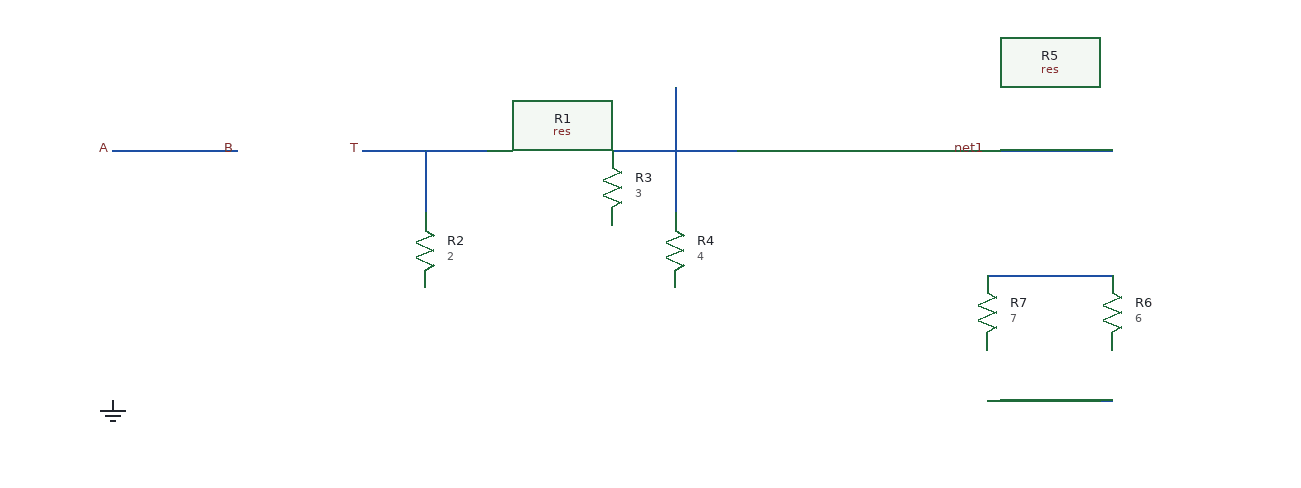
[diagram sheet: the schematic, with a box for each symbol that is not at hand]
v {xschem version=3.4.8RC file_version=1.3}
G {}
K {}
V {}
S {}
F {}
E {}
N 0 0 100 0 {}
C {lab_pin.sym} 0 0 0 0 {name=l1 lab=A}
C {lab_pin.sym} 100 0 0 0 {name=l2 lab=B}
C {res.sym} 50 30 0 0 {name=R1 value=1}
N 200 0 300 0 {}
N 250 0 250 50 {}
C {lab_pin.sym} 200 0 0 0 {name=l3 lab=T}
C {res.sym} 250 80 0 0 {name=R2 value=2}
N 400 0 500 0 {}
N 450 -50 450 50 {}
C {res.sym} 400 30 0 0 {name=R3 value=3}
C {res.sym} 450 80 0 0 {name=R4 value=4}
C {res.sym} 600 0 0 0 {name=R5 value=5}
N 700 0 800 0 {}
C {lab_pin.sym} 700 0 0 0 {name=l4 lab=net1}
N 700 100 800 100 {}
N 700 200 800 200 {}
C {res.sym} 800 130 0 0 {name=R6 value=6}
C {res.sym} 700 130 0 0 {name=R7 value=7}
C {gnd.sym} 0 200 0 0 {name=l5 lab=0}
